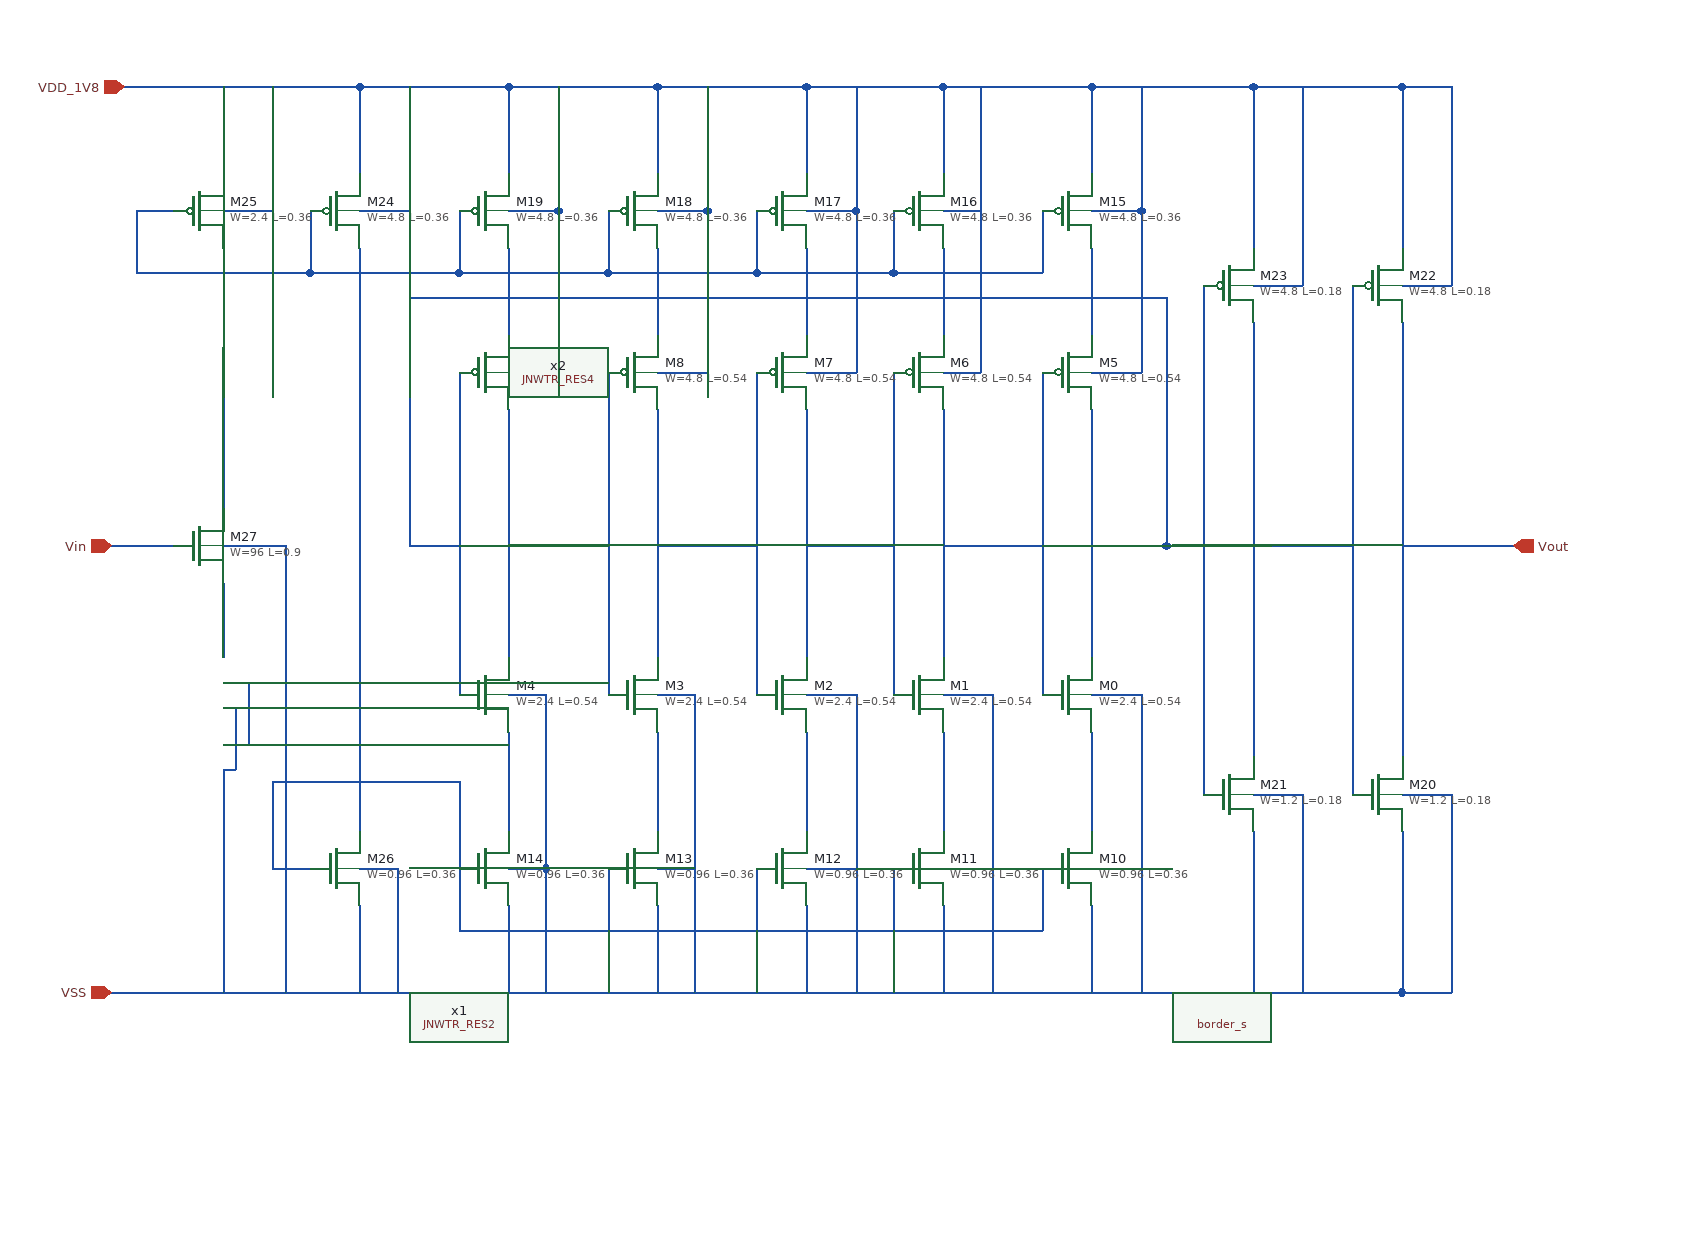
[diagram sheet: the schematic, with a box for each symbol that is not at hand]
v {xschem version=3.4.7 file_version=1.2}
G {}
K {}
V {}
S {}
E {}
N -470 -760 -470 -690 {lab=VDD_1V8}
N -550 -760 -460 -760 {lab=VDD_1V8}
N -460 -760 -360 -760 {lab=VDD_1V8}
N -360 -760 -360 -690 {lab=VDD_1V8}
N -240 -760 -240 -690 {lab=VDD_1V8}
N -360 -760 -240 -760 {lab=VDD_1V8}
N -120 -760 -120 -690 {lab=VDD_1V8}
N -240 -760 -120 -760 {lab=VDD_1V8}
N -0 -760 -0 -690 {lab=VDD_1V8}
N -120 -760 -0 -760 {lab=VDD_1V8}
N 110 -760 110 -690 {lab=VDD_1V8}
N 0 -760 110 -760 {lab=VDD_1V8}
N 230 -760 230 -690 {lab=VDD_1V8}
N 360 -760 360 -630 {lab=VDD_1V8}
N 480 -760 480 -640 {lab=VDD_1V8}
N 360 -760 480 -760 {lab=VDD_1V8}
N 480 -640 480 -630 {lab=VDD_1V8}
N -240 -630 -240 -560 {lab=#net1}
N -120 -630 -120 -570 {lab=#net2}
N -120 -570 -120 -560 {lab=#net2}
N -0 -630 -0 -560 {lab=#net3}
N 110 -630 110 -560 {lab=#net4}
N 230 -630 230 -560 {lab=#net5}
N -240 -500 -240 -300 {lab=#net6}
N -240 -240 -240 -170 {lab=#net7}
N -120 -500 -120 -300 {lab=#net8}
N -120 -240 -120 -160 {lab=#net9}
N -240 -170 -240 -160 {lab=#net7}
N -0 -500 -0 -300 {lab=#net10}
N -0 -240 0 -160 {lab=#net11}
N 110 -240 110 -160 {lab=#net12}
N 110 -500 110 -300 {lab=#net13}
N 230 -500 230 -300 {lab=#net14}
N 230 -240 230 -160 {lab=#net15}
N -560 -30 460 -30 {lab=VSS}
N 460 -30 470 -30 {lab=VSS}
N -240 -100 -240 -70 {lab=VSS}
N -240 -70 -240 -30 {lab=VSS}
N -120 -100 -120 -30 {lab=VSS}
N -0 -100 -0 -30 {lab=VSS}
N 110 -100 110 -30 {lab=VSS}
N 230 -100 230 -30 {lab=VSS}
N 360 -160 360 -30 {lab=VSS}
N -470 -360 -470 -320 {lab=#net16}
N -360 -240 -360 -230 {lab=#net17}
N -360 -230 -360 -220 {lab=#net17}
N -360 -630 -360 -240 {lab=#net17}
N -470 -630 -470 -420 {lab=#net18}
N -560 -390 -510 -390 {lab=Vin}
N -540 -660 -510 -660 {lab=#net18}
N -360 -220 -360 -160 {lab=#net17}
N -360 -100 -360 -30 {lab=VSS}
N -430 -200 -360 -200 {lab=#net17}
N -430 -200 -430 -130 {lab=#net17}
N -430 -130 -400 -130 {lab=#net17}
N -280 -530 -280 -270 {lab=#net14}
N -160 -530 -160 -270 {lab=#net6}
N -40 -530 -40 -270 {lab=#net8}
N 70 -530 70 -270 {lab=#net10}
N 190 -530 190 -270 {lab=#net13}
N -240 -390 -160 -390 {lab=#net6}
N -120 -390 -40 -390 {lab=#net8}
N -0 -390 70 -390 {lab=#net10}
N 110 -390 190 -390 {lab=#net13}
N 230 -390 290 -390 {lab=#net14}
N 290 -590 290 -390 {lab=#net14}
N -320 -590 290 -590 {lab=#net14}
N -320 -590 -320 -390 {lab=#net14}
N -320 -390 -280 -390 {lab=#net14}
N 320 -600 320 -190 {lab=#net14}
N 290 -390 320 -390 {lab=#net14}
N 360 -570 360 -220 {lab=#net19}
N 440 -600 440 -240 {lab=#net19}
N 480 -160 480 -30 {lab=VSS}
N 470 -30 480 -30 {lab=VSS}
N 440 -240 440 -190 {lab=#net19}
N 480 -570 480 -220 {lab=Vout}
N 360 -390 440 -390 {lab=#net19}
N 480 -390 570 -390 {lab=Vout}
N 110 -760 230 -760 {lab=VDD_1V8}
N 230 -760 360 -760 {lab=VDD_1V8}
N -470 -320 -470 -300 {lab=#net16}
N -470 -280 -450 -280 {lab=#net20}
N -450 -280 -450 -230 {lab=#net20}
N -470 -230 -450 -230 {lab=#net20}
N -470 -210 -470 -190 {lab=VSS}
N -470 -190 -470 -30 {lab=VSS}
N -470 -260 -460 -260 {lab=VSS}
N -460 -260 -460 -210 {lab=VSS}
N -470 -210 -460 -210 {lab=VSS}
N -400 -660 -400 -610 {lab=#net18}
N -400 -610 -280 -610 {lab=#net18}
N -280 -660 -280 -610 {lab=#net18}
N -280 -610 -160 -610 {lab=#net18}
N -160 -660 -160 -610 {lab=#net18}
N -160 -610 -40 -610 {lab=#net18}
N -40 -660 -40 -610 {lab=#net18}
N -40 -610 70 -610 {lab=#net18}
N 70 -660 70 -610 {lab=#net18}
N 70 -610 190 -610 {lab=#net18}
N 190 -660 190 -610 {lab=#net18}
N -470 -660 -430 -660 {lab=VDD_1V8}
N -430 -760 -430 -660 {lab=VDD_1V8}
N -360 -660 -320 -660 {lab=VDD_1V8}
N -320 -760 -320 -660 {lab=VDD_1V8}
N -240 -660 -200 -660 {lab=VDD_1V8}
N -200 -760 -200 -660 {lab=VDD_1V8}
N -120 -660 -80 -660 {lab=VDD_1V8}
N -80 -760 -80 -660 {lab=VDD_1V8}
N -0 -660 40 -660 {lab=VDD_1V8}
N 40 -760 40 -660 {lab=VDD_1V8}
N 230 -660 270 -660 {lab=VDD_1V8}
N 270 -760 270 -660 {lab=VDD_1V8}
N 360 -600 400 -600 {lab=VDD_1V8}
N 400 -760 400 -600 {lab=VDD_1V8}
N 480 -600 520 -600 {lab=VDD_1V8}
N 520 -760 520 -600 {lab=VDD_1V8}
N 480 -760 520 -760 {lab=VDD_1V8}
N -240 -530 -200 -530 {lab=VDD_1V8}
N -200 -660 -200 -530 {lab=VDD_1V8}
N -120 -530 -80 -530 {lab=VDD_1V8}
N -80 -660 -80 -530 {lab=VDD_1V8}
N 0 -530 40 -530 {lab=VDD_1V8}
N 40 -660 40 -530 {lab=VDD_1V8}
N 110 -530 140 -530 {lab=VDD_1V8}
N 140 -760 140 -530 {lab=VDD_1V8}
N 110 -660 140 -660 {lab=VDD_1V8}
N 230 -530 270 -530 {lab=VDD_1V8}
N 270 -660 270 -530 {lab=VDD_1V8}
N -440 -390 -430 -390 {lab=VSS}
N -280 -130 -280 -80 {lab=#net17}
N -280 -80 190 -80 {lab=#net17}
N 190 -130 190 -80 {lab=#net17}
N 70 -130 70 -80 {lab=#net17}
N -40 -130 -40 -80 {lab=#net17}
N -160 -130 -160 -80 {lab=#net17}
N -240 -130 -210 -130 {lab=VSS}
N -210 -130 -210 -30 {lab=VSS}
N -360 -130 -330 -130 {lab=VSS}
N -330 -130 -330 -30 {lab=VSS}
N -470 -390 -440 -390 {lab=VSS}
N -430 -390 -420 -390 {lab=VSS}
N -420 -390 -420 -30 {lab=VSS}
N -240 -270 -210 -270 {lab=VSS}
N -210 -270 -210 -130 {lab=VSS}
N -120 -270 -90 -270 {lab=VSS}
N -90 -270 -90 -30 {lab=VSS}
N -120 -130 -90 -130 {lab=VSS}
N -0 -270 40 -270 {lab=VSS}
N 40 -270 40 -30 {lab=VSS}
N 110 -270 150 -270 {lab=VSS}
N 150 -270 150 -30 {lab=VSS}
N 230 -270 270 -270 {lab=VSS}
N 270 -270 270 -30 {lab=VSS}
N 360 -190 400 -190 {lab=VSS}
N 400 -190 400 -30 {lab=VSS}
N -0 -130 40 -130 {lab=VSS}
N 110 -130 150 -130 {lab=VSS}
N 230 -130 270 -130 {lab=VSS}
N 480 -190 520 -190 {lab=VSS}
N 520 -190 520 -30 {lab=VSS}
N 480 -30 520 -30 {lab=VSS}
N -540 -660 -540 -610 {lab=#net18}
N -540 -610 -470 -610 {lab=#net18}
N -470 -610 -400 -610 {lab=#net18}
N -360 -200 -280 -200 {lab=#net17}
N -280 -200 -280 -130 {lab=#net17}
C {cborder/border_s.sym} 480 110 0 0 {
user="Nima"
company="PolitoLirmm"}
C {devices/ipin.sym} -550 -760 0 0 {name=p1 lab=VDD_1V8}
C {devices/ipin.sym} -560 -30 0 0 {name=p2 lab=VSS}
C {devices/ipin.sym} -560 -390 0 0 {name=p3 lab=Vin}
C {sky130_fd_pr/nfet_01v8.sym} -260 -270 0 0 {name=M4
W=2.4
L=0.54
nf=1 
mult=1
ad="expr('int((@nf + 1)/2) * @W / @nf * 0.29')"
pd="expr('2*int((@nf + 1)/2) * (@W / @nf + 0.29)')"
as="expr('int((@nf + 2)/2) * @W / @nf * 0.29')"
ps="expr('2*int((@nf + 2)/2) * (@W / @nf + 0.29)')"
nrd="expr('0.29 / @W ')" nrs="expr('0.29 / @W ')"
sa=0 sb=0 sd=0
model=nfet_01v8
spiceprefix=X
}
C {sky130_fd_pr/nfet_01v8.sym} -140 -270 0 0 {name=M3
W=2.4
L=0.54
nf=1 
mult=1
ad="expr('int((@nf + 1)/2) * @W / @nf * 0.29')"
pd="expr('2*int((@nf + 1)/2) * (@W / @nf + 0.29)')"
as="expr('int((@nf + 2)/2) * @W / @nf * 0.29')"
ps="expr('2*int((@nf + 2)/2) * (@W / @nf + 0.29)')"
nrd="expr('0.29 / @W ')" nrs="expr('0.29 / @W ')"
sa=0 sb=0 sd=0
model=nfet_01v8
spiceprefix=X
}
C {sky130_fd_pr/nfet_01v8.sym} -20 -270 0 0 {name=M2
W=2.4
L=0.54
nf=1 
mult=1
ad="expr('int((@nf + 1)/2) * @W / @nf * 0.29')"
pd="expr('2*int((@nf + 1)/2) * (@W / @nf + 0.29)')"
as="expr('int((@nf + 2)/2) * @W / @nf * 0.29')"
ps="expr('2*int((@nf + 2)/2) * (@W / @nf + 0.29)')"
nrd="expr('0.29 / @W ')" nrs="expr('0.29 / @W ')"
sa=0 sb=0 sd=0
model=nfet_01v8
spiceprefix=X
}
C {sky130_fd_pr/nfet_01v8.sym} 90 -270 0 0 {name=M1
W=2.4
L=0.54
nf=1 
mult=1
ad="expr('int((@nf + 1)/2) * @W / @nf * 0.29')"
pd="expr('2*int((@nf + 1)/2) * (@W / @nf + 0.29)')"
as="expr('int((@nf + 2)/2) * @W / @nf * 0.29')"
ps="expr('2*int((@nf + 2)/2) * (@W / @nf + 0.29)')"
nrd="expr('0.29 / @W ')" nrs="expr('0.29 / @W ')"
sa=0 sb=0 sd=0
model=nfet_01v8
spiceprefix=X
}
C {sky130_fd_pr/nfet_01v8.sym} 210 -270 0 0 {name=M0
W=2.4
L=0.54
nf=1 
mult=1
ad="expr('int((@nf + 1)/2) * @W / @nf * 0.29')"
pd="expr('2*int((@nf + 1)/2) * (@W / @nf + 0.29)')"
as="expr('int((@nf + 2)/2) * @W / @nf * 0.29')"
ps="expr('2*int((@nf + 2)/2) * (@W / @nf + 0.29)')"
nrd="expr('0.29 / @W ')" nrs="expr('0.29 / @W ')"
sa=0 sb=0 sd=0
model=nfet_01v8
spiceprefix=X
}
C {sky130_fd_pr/nfet_01v8.sym} -260 -130 0 0 {name=M14
W=0.96
L=0.36
nf=1 
mult=1
ad="expr('int((@nf + 1)/2) * @W / @nf * 0.29')"
pd="expr('2*int((@nf + 1)/2) * (@W / @nf + 0.29)')"
as="expr('int((@nf + 2)/2) * @W / @nf * 0.29')"
ps="expr('2*int((@nf + 2)/2) * (@W / @nf + 0.29)')"
nrd="expr('0.29 / @W ')" nrs="expr('0.29 / @W ')"
sa=0 sb=0 sd=0
model=nfet_01v8
spiceprefix=X
}
C {sky130_fd_pr/nfet_01v8.sym} -140 -130 0 0 {name=M13
W=0.96
L=0.36
nf=1 
mult=1
ad="expr('int((@nf + 1)/2) * @W / @nf * 0.29')"
pd="expr('2*int((@nf + 1)/2) * (@W / @nf + 0.29)')"
as="expr('int((@nf + 2)/2) * @W / @nf * 0.29')"
ps="expr('2*int((@nf + 2)/2) * (@W / @nf + 0.29)')"
nrd="expr('0.29 / @W ')" nrs="expr('0.29 / @W ')"
sa=0 sb=0 sd=0
model=nfet_01v8
spiceprefix=X
}
C {sky130_fd_pr/nfet_01v8.sym} -20 -130 0 0 {name=M12
W=0.96
L=0.36
nf=1 
mult=1
ad="expr('int((@nf + 1)/2) * @W / @nf * 0.29')"
pd="expr('2*int((@nf + 1)/2) * (@W / @nf + 0.29)')"
as="expr('int((@nf + 2)/2) * @W / @nf * 0.29')"
ps="expr('2*int((@nf + 2)/2) * (@W / @nf + 0.29)')"
nrd="expr('0.29 / @W ')" nrs="expr('0.29 / @W ')"
sa=0 sb=0 sd=0
model=nfet_01v8
spiceprefix=X
}
C {sky130_fd_pr/nfet_01v8.sym} 90 -130 0 0 {name=M11
W=0.96
L=0.36
nf=1 
mult=1
ad="expr('int((@nf + 1)/2) * @W / @nf * 0.29')"
pd="expr('2*int((@nf + 1)/2) * (@W / @nf + 0.29)')"
as="expr('int((@nf + 2)/2) * @W / @nf * 0.29')"
ps="expr('2*int((@nf + 2)/2) * (@W / @nf + 0.29)')"
nrd="expr('0.29 / @W ')" nrs="expr('0.29 / @W ')"
sa=0 sb=0 sd=0
model=nfet_01v8
spiceprefix=X
}
C {sky130_fd_pr/nfet_01v8.sym} 210 -130 0 0 {name=M10
W=0.96
L=0.36
nf=1 
mult=1
ad="expr('int((@nf + 1)/2) * @W / @nf * 0.29')"
pd="expr('2*int((@nf + 1)/2) * (@W / @nf + 0.29)')"
as="expr('int((@nf + 2)/2) * @W / @nf * 0.29')"
ps="expr('2*int((@nf + 2)/2) * (@W / @nf + 0.29)')"
nrd="expr('0.29 / @W ')" nrs="expr('0.29 / @W ')"
sa=0 sb=0 sd=0
model=nfet_01v8
spiceprefix=X
}
C {sky130_fd_pr/nfet_01v8.sym} 340 -190 0 0 {name=M21
W=1.2
L=0.18
nf=1 
mult=1
ad="expr('int((@nf + 1)/2) * @W / @nf * 0.29')"
pd="expr('2*int((@nf + 1)/2) * (@W / @nf + 0.29)')"
as="expr('int((@nf + 2)/2) * @W / @nf * 0.29')"
ps="expr('2*int((@nf + 2)/2) * (@W / @nf + 0.29)')"
nrd="expr('0.29 / @W ')" nrs="expr('0.29 / @W ')"
sa=0 sb=0 sd=0
model=nfet_01v8
spiceprefix=X
}
C {sky130_fd_pr/nfet_01v8.sym} 460 -190 0 0 {name=M20
W=1.2
L=0.18
nf=1 
mult=1
ad="expr('int((@nf + 1)/2) * @W / @nf * 0.29')"
pd="expr('2*int((@nf + 1)/2) * (@W / @nf + 0.29)')"
as="expr('int((@nf + 2)/2) * @W / @nf * 0.29')"
ps="expr('2*int((@nf + 2)/2) * (@W / @nf + 0.29)')"
nrd="expr('0.29 / @W ')" nrs="expr('0.29 / @W ')"
sa=0 sb=0 sd=0
model=nfet_01v8
spiceprefix=X
}
C {sky130_fd_pr/nfet_01v8.sym} -380 -130 0 0 {name=M26
W=0.96
L=0.36
nf=1
mult=1
ad="expr('int((@nf + 1)/2) * @W / @nf * 0.29')"
pd="expr('2*int((@nf + 1)/2) * (@W / @nf + 0.29)')"
as="expr('int((@nf + 2)/2) * @W / @nf * 0.29')"
ps="expr('2*int((@nf + 2)/2) * (@W / @nf + 0.29)')"
nrd="expr('0.29 / @W ')" nrs="expr('0.29 / @W ')"
sa=0 sb=0 sd=0
model=nfet_01v8
spiceprefix=X
}
C {sky130_fd_pr/nfet_01v8.sym} -490 -390 0 0 {name=M27
W=96
L=0.9
nf=1 
mult=1
ad="expr('int((@nf + 1)/2) * @W / @nf * 0.29')"
pd="expr('2*int((@nf + 1)/2) * (@W / @nf + 0.29)')"
as="expr('int((@nf + 2)/2) * @W / @nf * 0.29')"
ps="expr('2*int((@nf + 2)/2) * (@W / @nf + 0.29)')"
nrd="expr('0.29 / @W ')" nrs="expr('0.29 / @W ')"
sa=0 sb=0 sd=0
model=nfet_01v8
spiceprefix=X
}
C {sky130_fd_pr/pfet_01v8.sym} -260 -530 0 0 {name=M9
W=4.8
L=0.54
nf=1
mult=1
ad="expr('int((@nf + 1)/2) * @W / @nf * 0.29')"
pd="expr('2*int((@nf + 1)/2) * (@W / @nf + 0.29)')"
as="expr('int((@nf + 2)/2) * @W / @nf * 0.29')"
ps="expr('2*int((@nf + 2)/2) * (@W / @nf + 0.29)')"
nrd="expr('0.29 / @W ')" nrs="expr('0.29 / @W ')"
sa=0 sb=0 sd=0
model=pfet_01v8
spiceprefix=X
}
C {sky130_fd_pr/pfet_01v8.sym} -140 -530 0 0 {name=M8
W=4.8
L=0.54
nf=1
mult=1
ad="expr('int((@nf + 1)/2) * @W / @nf * 0.29')"
pd="expr('2*int((@nf + 1)/2) * (@W / @nf + 0.29)')"
as="expr('int((@nf + 2)/2) * @W / @nf * 0.29')"
ps="expr('2*int((@nf + 2)/2) * (@W / @nf + 0.29)')"
nrd="expr('0.29 / @W ')" nrs="expr('0.29 / @W ')"
sa=0 sb=0 sd=0
model=pfet_01v8
spiceprefix=X
}
C {sky130_fd_pr/pfet_01v8.sym} -20 -530 0 0 {name=M7
W=4.8
L=0.54
nf=1
mult=1
ad="expr('int((@nf + 1)/2) * @W / @nf * 0.29')"
pd="expr('2*int((@nf + 1)/2) * (@W / @nf + 0.29)')"
as="expr('int((@nf + 2)/2) * @W / @nf * 0.29')"
ps="expr('2*int((@nf + 2)/2) * (@W / @nf + 0.29)')"
nrd="expr('0.29 / @W ')" nrs="expr('0.29 / @W ')"
sa=0 sb=0 sd=0
model=pfet_01v8
spiceprefix=X
}
C {sky130_fd_pr/pfet_01v8.sym} 90 -530 0 0 {name=M6
W=4.8
L=0.54
nf=1
mult=1
ad="expr('int((@nf + 1)/2) * @W / @nf * 0.29')"
pd="expr('2*int((@nf + 1)/2) * (@W / @nf + 0.29)')"
as="expr('int((@nf + 2)/2) * @W / @nf * 0.29')"
ps="expr('2*int((@nf + 2)/2) * (@W / @nf + 0.29)')"
nrd="expr('0.29 / @W ')" nrs="expr('0.29 / @W ')"
sa=0 sb=0 sd=0
model=pfet_01v8
spiceprefix=X
}
C {sky130_fd_pr/pfet_01v8.sym} 210 -530 0 0 {name=M5
W=4.8
L=0.54
nf=1
mult=1
ad="expr('int((@nf + 1)/2) * @W / @nf * 0.29')"
pd="expr('2*int((@nf + 1)/2) * (@W / @nf + 0.29)')"
as="expr('int((@nf + 2)/2) * @W / @nf * 0.29')"
ps="expr('2*int((@nf + 2)/2) * (@W / @nf + 0.29)')"
nrd="expr('0.29 / @W ')" nrs="expr('0.29 / @W ')"
sa=0 sb=0 sd=0
model=pfet_01v8
spiceprefix=X
}
C {sky130_fd_pr/pfet_01v8.sym} -260 -660 0 0 {name=M19
W=4.8
L=0.36
nf=1
mult=1
ad="expr('int((@nf + 1)/2) * @W / @nf * 0.29')"
pd="expr('2*int((@nf + 1)/2) * (@W / @nf + 0.29)')"
as="expr('int((@nf + 2)/2) * @W / @nf * 0.29')"
ps="expr('2*int((@nf + 2)/2) * (@W / @nf + 0.29)')"
nrd="expr('0.29 / @W ')" nrs="expr('0.29 / @W ')"
sa=0 sb=0 sd=0
model=pfet_01v8
spiceprefix=X
}
C {sky130_fd_pr/pfet_01v8.sym} -140 -660 0 0 {name=M18
W=4.8
L=0.36
nf=1
mult=1
ad="expr('int((@nf + 1)/2) * @W / @nf * 0.29')"
pd="expr('2*int((@nf + 1)/2) * (@W / @nf + 0.29)')"
as="expr('int((@nf + 2)/2) * @W / @nf * 0.29')"
ps="expr('2*int((@nf + 2)/2) * (@W / @nf + 0.29)')"
nrd="expr('0.29 / @W ')" nrs="expr('0.29 / @W ')"
sa=0 sb=0 sd=0
model=pfet_01v8
spiceprefix=X
}
C {sky130_fd_pr/pfet_01v8.sym} -20 -660 0 0 {name=M17
W=4.8
L=0.36
nf=1
mult=1
ad="expr('int((@nf + 1)/2) * @W / @nf * 0.29')"
pd="expr('2*int((@nf + 1)/2) * (@W / @nf + 0.29)')"
as="expr('int((@nf + 2)/2) * @W / @nf * 0.29')"
ps="expr('2*int((@nf + 2)/2) * (@W / @nf + 0.29)')"
nrd="expr('0.29 / @W ')" nrs="expr('0.29 / @W ')"
sa=0 sb=0 sd=0
model=pfet_01v8
spiceprefix=X
}
C {sky130_fd_pr/pfet_01v8.sym} 90 -660 0 0 {name=M16
W=4.8
L=0.36
nf=1
mult=1
ad="expr('int((@nf + 1)/2) * @W / @nf * 0.29')"
pd="expr('2*int((@nf + 1)/2) * (@W / @nf + 0.29)')"
as="expr('int((@nf + 2)/2) * @W / @nf * 0.29')"
ps="expr('2*int((@nf + 2)/2) * (@W / @nf + 0.29)')"
nrd="expr('0.29 / @W ')" nrs="expr('0.29 / @W ')"
sa=0 sb=0 sd=0
model=pfet_01v8
spiceprefix=X
}
C {sky130_fd_pr/pfet_01v8.sym} 210 -660 0 0 {name=M15
W=4.8
L=0.36
nf=1
mult=1
ad="expr('int((@nf + 1)/2) * @W / @nf * 0.29')"
pd="expr('2*int((@nf + 1)/2) * (@W / @nf + 0.29)')"
as="expr('int((@nf + 2)/2) * @W / @nf * 0.29')"
ps="expr('2*int((@nf + 2)/2) * (@W / @nf + 0.29)')"
nrd="expr('0.29 / @W ')" nrs="expr('0.29 / @W ')"
sa=0 sb=0 sd=0
model=pfet_01v8
spiceprefix=X
}
C {sky130_fd_pr/pfet_01v8.sym} 340 -600 0 0 {name=M23
W=4.8
L=0.18
nf=1
mult=1
ad="expr('int((@nf + 1)/2) * @W / @nf * 0.29')"
pd="expr('2*int((@nf + 1)/2) * (@W / @nf + 0.29)')"
as="expr('int((@nf + 2)/2) * @W / @nf * 0.29')"
ps="expr('2*int((@nf + 2)/2) * (@W / @nf + 0.29)')"
nrd="expr('0.29 / @W ')" nrs="expr('0.29 / @W ')"
sa=0 sb=0 sd=0
model=pfet_01v8
spiceprefix=X
}
C {sky130_fd_pr/pfet_01v8.sym} 460 -600 0 0 {name=M22
W=4.8
L=0.18
nf=1
mult=1
ad="expr('int((@nf + 1)/2) * @W / @nf * 0.29')"
pd="expr('2*int((@nf + 1)/2) * (@W / @nf + 0.29)')"
as="expr('int((@nf + 2)/2) * @W / @nf * 0.29')"
ps="expr('2*int((@nf + 2)/2) * (@W / @nf + 0.29)')"
nrd="expr('0.29 / @W ')" nrs="expr('0.29 / @W ')"
sa=0 sb=0 sd=0
model=pfet_01v8
spiceprefix=X
}
C {sky130_fd_pr/pfet_01v8.sym} -380 -660 0 0 {name=M24
W=4.8
L=0.36
nf=1
mult=1
ad="expr('int((@nf + 1)/2) * @W / @nf * 0.29')"
pd="expr('2*int((@nf + 1)/2) * (@W / @nf + 0.29)')"
as="expr('int((@nf + 2)/2) * @W / @nf * 0.29')"
ps="expr('2*int((@nf + 2)/2) * (@W / @nf + 0.29)')"
nrd="expr('0.29 / @W ')" nrs="expr('0.29 / @W ')"
sa=0 sb=0 sd=0
model=pfet_01v8
spiceprefix=X
}
C {sky130_fd_pr/pfet_01v8.sym} -490 -660 0 0 {name=M25
W=2.4
L=0.36
nf=1
mult=1
ad="expr('int((@nf + 1)/2) * @W / @nf * 0.29')"
pd="expr('2*int((@nf + 1)/2) * (@W / @nf + 0.29)')"
as="expr('int((@nf + 2)/2) * @W / @nf * 0.29')"
ps="expr('2*int((@nf + 2)/2) * (@W / @nf + 0.29)')"
nrd="expr('0.29 / @W ')" nrs="expr('0.29 / @W ')"
sa=0 sb=0 sd=0
model=pfet_01v8
spiceprefix=X
}
C {devices/opin.sym} 570 -390 0 0 {name=p4 lab=Vout}
C {JNW_TR_SKY130A/JNWTR_RES2.sym} -490 -230 0 1 {name=x1 }
C {JNW_TR_SKY130A/JNWTR_RES4.sym} -490 -300 0 1 {name=x2 }
